VERSION 5.8 ;
BUSBITCHARS "[]" ;
DIVIDERCHAR "/" ;
UNITS
    DATABASE MICRONS 1000 ;
END UNITS

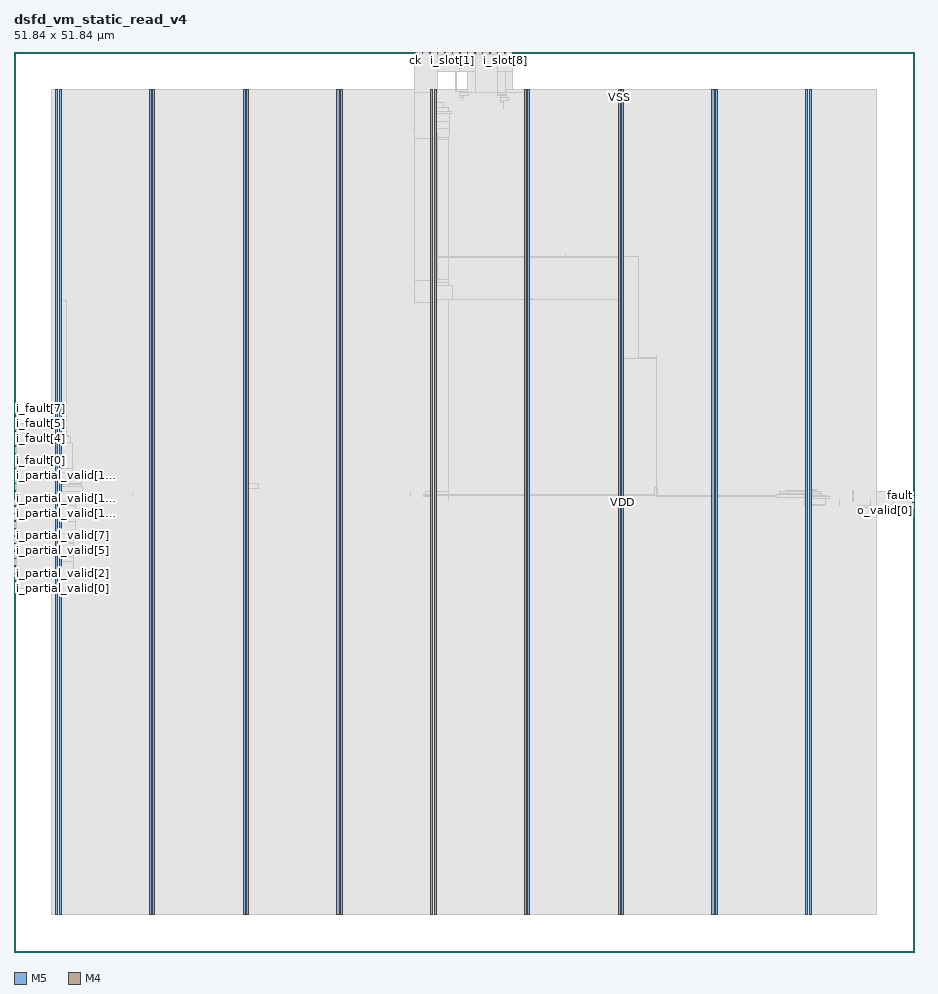
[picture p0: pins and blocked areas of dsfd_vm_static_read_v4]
MACRO dsfd_vm_static_read_v4
  FOREIGN dsfd_vm_static_read_v4 0 0 ;
  CLASS BLOCK ;
  SIZE 51.84 BY 51.84 ;
  PIN ck
    DIRECTION INPUT ;
    USE SIGNAL ;
    PORT
      LAYER M5 ;
        RECT  23.088 51.756 23.112 51.84 ;
    END
  END ck
  PIN fault
    DIRECTION OUTPUT ;
    USE SIGNAL ;
    PORT
      LAYER M4 ;
        RECT  51.756 26.304 51.84 26.328 ;
    END
  END fault
  PIN i_expected[0]
    DIRECTION INPUT ;
    USE SIGNAL ;
    PORT
      LAYER M5 ;
        RECT  23.952 51.756 23.976 51.84 ;
    END
  END i_expected[0]
  PIN i_expected[1]
    DIRECTION INPUT ;
    USE SIGNAL ;
    PORT
      LAYER M5 ;
        RECT  24.384 51.756 24.408 51.84 ;
    END
  END i_expected[1]
  PIN i_fault[0]
    DIRECTION INPUT ;
    USE SIGNAL ;
    PORT
      LAYER M4 ;
        RECT  0 27.84 0.084 27.864 ;
    END
  END i_fault[0]
  PIN i_fault[1]
    DIRECTION INPUT ;
    USE SIGNAL ;
    PORT
      LAYER M4 ;
        RECT  0 28.272 0.084 28.296 ;
    END
  END i_fault[1]
  PIN i_fault[2]
    DIRECTION INPUT ;
    USE SIGNAL ;
    PORT
      LAYER M4 ;
        RECT  0 28.704 0.084 28.728 ;
    END
  END i_fault[2]
  PIN i_fault[3]
    DIRECTION INPUT ;
    USE SIGNAL ;
    PORT
      LAYER M4 ;
        RECT  0 29.136 0.084 29.16 ;
    END
  END i_fault[3]
  PIN i_fault[4]
    DIRECTION INPUT ;
    USE SIGNAL ;
    PORT
      LAYER M4 ;
        RECT  0 29.568 0.084 29.592 ;
    END
  END i_fault[4]
  PIN i_fault[5]
    DIRECTION INPUT ;
    USE SIGNAL ;
    PORT
      LAYER M4 ;
        RECT  0 30 0.084 30.024 ;
    END
  END i_fault[5]
  PIN i_fault[6]
    DIRECTION INPUT ;
    USE SIGNAL ;
    PORT
      LAYER M4 ;
        RECT  0 30.432 0.084 30.456 ;
    END
  END i_fault[6]
  PIN i_fault[7]
    DIRECTION INPUT ;
    USE SIGNAL ;
    PORT
      LAYER M4 ;
        RECT  0 30.864 0.084 30.888 ;
    END
  END i_fault[7]
  PIN i_partial_valid[0]
    DIRECTION INPUT ;
    USE SIGNAL ;
    PORT
      LAYER M4 ;
        RECT  0 20.928 0.084 20.952 ;
    END
  END i_partial_valid[0]
  PIN i_partial_valid[10]
    DIRECTION INPUT ;
    USE SIGNAL ;
    PORT
      LAYER M4 ;
        RECT  0 25.248 0.084 25.272 ;
    END
  END i_partial_valid[10]
  PIN i_partial_valid[11]
    DIRECTION INPUT ;
    USE SIGNAL ;
    PORT
      LAYER M4 ;
        RECT  0 25.68 0.084 25.704 ;
    END
  END i_partial_valid[11]
  PIN i_partial_valid[12]
    DIRECTION INPUT ;
    USE SIGNAL ;
    PORT
      LAYER M4 ;
        RECT  0 26.112 0.084 26.136 ;
    END
  END i_partial_valid[12]
  PIN i_partial_valid[13]
    DIRECTION INPUT ;
    USE SIGNAL ;
    PORT
      LAYER M4 ;
        RECT  0 26.544 0.084 26.568 ;
    END
  END i_partial_valid[13]
  PIN i_partial_valid[14]
    DIRECTION INPUT ;
    USE SIGNAL ;
    PORT
      LAYER M4 ;
        RECT  0 26.976 0.084 27 ;
    END
  END i_partial_valid[14]
  PIN i_partial_valid[15]
    DIRECTION INPUT ;
    USE SIGNAL ;
    PORT
      LAYER M4 ;
        RECT  0 27.408 0.084 27.432 ;
    END
  END i_partial_valid[15]
  PIN i_partial_valid[1]
    DIRECTION INPUT ;
    USE SIGNAL ;
    PORT
      LAYER M4 ;
        RECT  0 21.36 0.084 21.384 ;
    END
  END i_partial_valid[1]
  PIN i_partial_valid[2]
    DIRECTION INPUT ;
    USE SIGNAL ;
    PORT
      LAYER M4 ;
        RECT  0 21.792 0.084 21.816 ;
    END
  END i_partial_valid[2]
  PIN i_partial_valid[3]
    DIRECTION INPUT ;
    USE SIGNAL ;
    PORT
      LAYER M4 ;
        RECT  0 22.224 0.084 22.248 ;
    END
  END i_partial_valid[3]
  PIN i_partial_valid[4]
    DIRECTION INPUT ;
    USE SIGNAL ;
    PORT
      LAYER M4 ;
        RECT  0 22.656 0.084 22.68 ;
    END
  END i_partial_valid[4]
  PIN i_partial_valid[5]
    DIRECTION INPUT ;
    USE SIGNAL ;
    PORT
      LAYER M4 ;
        RECT  0 23.088 0.084 23.112 ;
    END
  END i_partial_valid[5]
  PIN i_partial_valid[6]
    DIRECTION INPUT ;
    USE SIGNAL ;
    PORT
      LAYER M4 ;
        RECT  0 23.52 0.084 23.544 ;
    END
  END i_partial_valid[6]
  PIN i_partial_valid[7]
    DIRECTION INPUT ;
    USE SIGNAL ;
    PORT
      LAYER M4 ;
        RECT  0 23.952 0.084 23.976 ;
    END
  END i_partial_valid[7]
  PIN i_partial_valid[8]
    DIRECTION INPUT ;
    USE SIGNAL ;
    PORT
      LAYER M4 ;
        RECT  0 24.384 0.084 24.408 ;
    END
  END i_partial_valid[8]
  PIN i_partial_valid[9]
    DIRECTION INPUT ;
    USE SIGNAL ;
    PORT
      LAYER M4 ;
        RECT  0 24.816 0.084 24.84 ;
    END
  END i_partial_valid[9]
  PIN i_slot[0]
    DIRECTION INPUT ;
    USE SIGNAL ;
    PORT
      LAYER M5 ;
        RECT  24.816 51.756 24.84 51.84 ;
    END
  END i_slot[0]
  PIN i_slot[1]
    DIRECTION INPUT ;
    USE SIGNAL ;
    PORT
      LAYER M5 ;
        RECT  25.248 51.756 25.272 51.84 ;
    END
  END i_slot[1]
  PIN i_slot[2]
    DIRECTION INPUT ;
    USE SIGNAL ;
    PORT
      LAYER M5 ;
        RECT  25.68 51.756 25.704 51.84 ;
    END
  END i_slot[2]
  PIN i_slot[3]
    DIRECTION INPUT ;
    USE SIGNAL ;
    PORT
      LAYER M5 ;
        RECT  26.112 51.756 26.136 51.84 ;
    END
  END i_slot[3]
  PIN i_slot[4]
    DIRECTION INPUT ;
    USE SIGNAL ;
    PORT
      LAYER M5 ;
        RECT  26.544 51.756 26.568 51.84 ;
    END
  END i_slot[4]
  PIN i_slot[5]
    DIRECTION INPUT ;
    USE SIGNAL ;
    PORT
      LAYER M5 ;
        RECT  26.976 51.756 27 51.84 ;
    END
  END i_slot[5]
  PIN i_slot[6]
    DIRECTION INPUT ;
    USE SIGNAL ;
    PORT
      LAYER M5 ;
        RECT  27.408 51.756 27.432 51.84 ;
    END
  END i_slot[6]
  PIN i_slot[7]
    DIRECTION INPUT ;
    USE SIGNAL ;
    PORT
      LAYER M5 ;
        RECT  27.84 51.756 27.864 51.84 ;
    END
  END i_slot[7]
  PIN i_slot[8]
    DIRECTION INPUT ;
    USE SIGNAL ;
    PORT
      LAYER M5 ;
        RECT  28.272 51.756 28.296 51.84 ;
    END
  END i_slot[8]
  PIN i_slot[9]
    DIRECTION INPUT ;
    USE SIGNAL ;
    PORT
      LAYER M5 ;
        RECT  28.704 51.756 28.728 51.84 ;
    END
  END i_slot[9]
  PIN o_valid[0]
    DIRECTION OUTPUT ;
    USE SIGNAL ;
    PORT
      LAYER M4 ;
        RECT  51.756 25.44 51.84 25.464 ;
    END
  END o_valid[0]
  PIN o_valid[1]
    DIRECTION OUTPUT ;
    USE SIGNAL ;
    PORT
      LAYER M4 ;
        RECT  51.756 25.872 51.84 25.896 ;
    END
  END o_valid[1]
  PIN rst_n
    DIRECTION INPUT ;
    USE SIGNAL ;
    PORT
      LAYER M5 ;
        RECT  23.52 51.756 23.544 51.84 ;
    END
  END rst_n
  PIN VDD
    DIRECTION INOUT ;
    USE POWER ;
    PORT
      LAYER M5 ;
        RECT  45.792 2.151 45.912 49.689 ;
        RECT  40.392 2.151 40.512 49.689 ;
        RECT  34.992 2.151 35.112 49.689 ;
        RECT  29.592 2.151 29.712 49.689 ;
        RECT  24.192 2.151 24.312 49.689 ;
        RECT  18.792 2.151 18.912 49.689 ;
        RECT  13.392 2.151 13.512 49.689 ;
        RECT  7.992 2.151 8.112 49.689 ;
        RECT  2.592 2.151 2.712 49.689 ;
    END
  END VDD
  PIN VSS
    DIRECTION INOUT ;
    USE GROUND ;
    PORT
      LAYER M5 ;
        RECT  45.6 2.137 45.72 49.703 ;
        RECT  40.2 2.137 40.32 49.703 ;
        RECT  34.8 2.137 34.92 49.703 ;
        RECT  29.4 2.137 29.52 49.703 ;
        RECT  24 2.137 24.12 49.703 ;
        RECT  18.6 2.137 18.72 49.703 ;
        RECT  13.2 2.137 13.32 49.703 ;
        RECT  7.8 2.137 7.92 49.703 ;
        RECT  2.4 2.137 2.52 49.703 ;
    END
  END VSS
  # OT_OBS_CLOSED layer=M5 d_um=1.536 added=11
  OBS
    LAYER RVTN ;
     RECT  2.16 2.16 49.68 2.295 ;
     RECT  2.16 2.565 49.68 2.835 ;
     RECT  2.16 3.105 49.68 3.375 ;
     RECT  2.16 3.645 49.68 3.915 ;
     RECT  2.16 4.185 49.68 4.455 ;
     RECT  2.16 4.725 49.68 4.995 ;
     RECT  2.16 5.265 49.68 5.535 ;
     RECT  2.16 5.805 49.68 6.075 ;
     RECT  2.16 6.345 49.68 6.615 ;
     RECT  2.16 6.885 49.68 7.155 ;
     RECT  2.16 7.425 49.68 7.695 ;
     RECT  2.16 7.965 49.68 8.235 ;
     RECT  2.16 8.505 49.68 8.775 ;
     RECT  2.16 9.045 49.68 9.315 ;
     RECT  2.16 9.585 49.68 9.855 ;
     RECT  2.16 10.125 49.68 10.395 ;
     RECT  2.16 10.665 49.68 10.935 ;
     RECT  2.16 11.205 49.68 11.475 ;
     RECT  2.16 11.745 49.68 12.015 ;
     RECT  2.16 12.285 49.68 12.555 ;
     RECT  2.16 12.825 49.68 13.095 ;
     RECT  2.16 13.365 49.68 13.635 ;
     RECT  2.16 13.905 49.68 14.175 ;
     RECT  2.16 14.445 49.68 14.715 ;
     RECT  2.16 14.985 49.68 15.255 ;
     RECT  2.16 15.525 49.68 15.795 ;
     RECT  2.16 16.065 49.68 16.335 ;
     RECT  2.16 16.605 49.68 16.875 ;
     RECT  2.16 17.145 49.68 17.415 ;
     RECT  2.16 17.685 49.68 17.955 ;
     RECT  2.16 18.225 49.68 18.495 ;
     RECT  2.16 18.765 49.68 19.035 ;
     RECT  2.16 19.305 49.68 19.575 ;
     RECT  2.16 19.845 49.68 20.115 ;
     RECT  2.16 20.385 49.68 20.655 ;
     RECT  2.16 20.925 49.68 21.195 ;
     RECT  2.16 21.465 49.68 21.735 ;
     RECT  2.16 22.005 49.68 22.275 ;
     RECT  2.16 22.545 49.68 22.815 ;
     RECT  2.16 23.085 49.68 23.355 ;
     RECT  2.16 23.625 49.68 23.895 ;
     RECT  2.16 24.165 49.68 24.435 ;
     RECT  2.16 24.705 49.68 24.975 ;
     RECT  2.16 25.245 49.68 25.515 ;
     RECT  2.16 25.785 49.68 26.055 ;
     RECT  2.16 26.325 49.68 26.595 ;
     RECT  2.16 26.865 49.68 27.135 ;
     RECT  2.16 27.405 49.68 27.675 ;
     RECT  2.16 27.945 49.68 28.215 ;
     RECT  2.16 28.485 49.68 28.755 ;
     RECT  2.16 29.025 49.68 29.295 ;
     RECT  2.16 29.565 49.68 29.835 ;
     RECT  2.16 30.105 49.68 30.375 ;
     RECT  2.16 30.645 49.68 30.915 ;
     RECT  2.16 31.185 49.68 31.455 ;
     RECT  2.16 31.725 49.68 31.995 ;
     RECT  2.16 32.265 49.68 32.535 ;
     RECT  2.16 32.805 49.68 33.075 ;
     RECT  2.16 33.345 49.68 33.615 ;
     RECT  2.16 33.885 49.68 34.155 ;
     RECT  2.16 34.425 49.68 34.695 ;
     RECT  2.16 34.965 49.68 35.235 ;
     RECT  2.16 35.505 49.68 35.775 ;
     RECT  2.16 36.045 49.68 36.315 ;
     RECT  2.16 36.585 49.68 36.855 ;
     RECT  2.16 37.125 49.68 37.395 ;
     RECT  2.16 37.665 49.68 37.935 ;
     RECT  2.16 38.205 49.68 38.475 ;
     RECT  2.16 38.745 49.68 39.015 ;
     RECT  2.16 39.285 49.68 39.555 ;
     RECT  2.16 39.825 49.68 40.095 ;
     RECT  2.16 40.365 49.68 40.635 ;
     RECT  2.16 40.905 49.68 41.175 ;
     RECT  2.16 41.445 49.68 41.715 ;
     RECT  2.16 41.985 49.68 42.255 ;
     RECT  2.16 42.525 49.68 42.795 ;
     RECT  2.16 43.065 49.68 43.335 ;
     RECT  2.16 43.605 49.68 43.875 ;
     RECT  2.16 44.145 49.68 44.415 ;
     RECT  2.16 44.685 49.68 44.955 ;
     RECT  2.16 45.225 49.68 45.495 ;
     RECT  2.16 45.765 49.68 46.035 ;
     RECT  2.16 46.305 49.68 46.575 ;
     RECT  2.16 46.845 49.68 47.115 ;
     RECT  2.16 47.385 49.68 47.655 ;
     RECT  2.16 47.925 49.68 48.195 ;
     RECT  2.16 48.465 49.68 48.735 ;
     RECT  2.16 49.005 49.68 49.275 ;
     RECT  2.16 49.545 49.68 49.68 ;
    LAYER RVTP ;
     RECT  2.16 2.295 49.68 2.565 ;
     RECT  2.16 2.835 49.68 3.105 ;
     RECT  2.16 3.375 49.68 3.645 ;
     RECT  2.16 3.915 49.68 4.185 ;
     RECT  2.16 4.455 49.68 4.725 ;
     RECT  2.16 4.995 49.68 5.265 ;
     RECT  2.16 5.535 49.68 5.805 ;
     RECT  2.16 6.075 49.68 6.345 ;
     RECT  2.16 6.615 49.68 6.885 ;
     RECT  2.16 7.155 49.68 7.425 ;
     RECT  2.16 7.695 49.68 7.965 ;
     RECT  2.16 8.235 49.68 8.505 ;
     RECT  2.16 8.775 49.68 9.045 ;
     RECT  2.16 9.315 49.68 9.585 ;
     RECT  2.16 9.855 49.68 10.125 ;
     RECT  2.16 10.395 49.68 10.665 ;
     RECT  2.16 10.935 49.68 11.205 ;
     RECT  2.16 11.475 49.68 11.745 ;
     RECT  2.16 12.015 49.68 12.285 ;
     RECT  2.16 12.555 49.68 12.825 ;
     RECT  2.16 13.095 49.68 13.365 ;
     RECT  2.16 13.635 49.68 13.905 ;
     RECT  2.16 14.175 49.68 14.445 ;
     RECT  2.16 14.715 49.68 14.985 ;
     RECT  2.16 15.255 49.68 15.525 ;
     RECT  2.16 15.795 49.68 16.065 ;
     RECT  2.16 16.335 49.68 16.605 ;
     RECT  2.16 16.875 49.68 17.145 ;
     RECT  2.16 17.415 49.68 17.685 ;
     RECT  2.16 17.955 49.68 18.225 ;
     RECT  2.16 18.495 49.68 18.765 ;
     RECT  2.16 19.035 49.68 19.305 ;
     RECT  2.16 19.575 49.68 19.845 ;
     RECT  2.16 20.115 49.68 20.385 ;
     RECT  2.16 20.655 49.68 20.925 ;
     RECT  2.16 21.195 49.68 21.465 ;
     RECT  2.16 21.735 49.68 22.005 ;
     RECT  2.16 22.275 49.68 22.545 ;
     RECT  2.16 22.815 49.68 23.085 ;
     RECT  2.16 23.355 49.68 23.625 ;
     RECT  2.16 23.895 49.68 24.165 ;
     RECT  2.16 24.435 49.68 24.705 ;
     RECT  2.16 24.975 49.68 25.245 ;
     RECT  2.16 25.515 49.68 25.785 ;
     RECT  2.16 26.055 49.68 26.325 ;
     RECT  2.16 26.595 49.68 26.865 ;
     RECT  2.16 27.135 49.68 27.405 ;
     RECT  2.16 27.675 49.68 27.945 ;
     RECT  2.16 28.215 49.68 28.485 ;
     RECT  2.16 28.755 49.68 29.025 ;
     RECT  2.16 29.295 49.68 29.565 ;
     RECT  2.16 29.835 49.68 30.105 ;
     RECT  2.16 30.375 49.68 30.645 ;
     RECT  2.16 30.915 49.68 31.185 ;
     RECT  2.16 31.455 49.68 31.725 ;
     RECT  2.16 31.995 49.68 32.265 ;
     RECT  2.16 32.535 49.68 32.805 ;
     RECT  2.16 33.075 49.68 33.345 ;
     RECT  2.16 33.615 49.68 33.885 ;
     RECT  2.16 34.155 49.68 34.425 ;
     RECT  2.16 34.695 49.68 34.965 ;
     RECT  2.16 35.235 49.68 35.505 ;
     RECT  2.16 35.775 49.68 36.045 ;
     RECT  2.16 36.315 49.68 36.585 ;
     RECT  2.16 36.855 49.68 37.125 ;
     RECT  2.16 37.395 49.68 37.665 ;
     RECT  2.16 37.935 49.68 38.205 ;
     RECT  2.16 38.475 49.68 38.745 ;
     RECT  2.16 39.015 49.68 39.285 ;
     RECT  2.16 39.555 49.68 39.825 ;
     RECT  2.16 40.095 49.68 40.365 ;
     RECT  2.16 40.635 49.68 40.905 ;
     RECT  2.16 41.175 49.68 41.445 ;
     RECT  2.16 41.715 49.68 41.985 ;
     RECT  2.16 42.255 49.68 42.525 ;
     RECT  2.16 42.795 49.68 43.065 ;
     RECT  2.16 43.335 49.68 43.605 ;
     RECT  2.16 43.875 49.68 44.145 ;
     RECT  2.16 44.415 49.68 44.685 ;
     RECT  2.16 44.955 49.68 45.225 ;
     RECT  2.16 45.495 49.68 45.765 ;
     RECT  2.16 46.035 49.68 46.305 ;
     RECT  2.16 46.575 49.68 46.845 ;
     RECT  2.16 47.115 49.68 47.385 ;
     RECT  2.16 47.655 49.68 47.925 ;
     RECT  2.16 48.195 49.68 48.465 ;
     RECT  2.16 48.735 49.68 49.005 ;
     RECT  2.16 49.275 49.68 49.545 ;
    LAYER M1 ;
     RECT  2.16 2.151 49.68 49.689 ;
    LAYER M2 ;
     RECT  0.103 29.034 0.139 29.052 ;
     RECT  0.103 25.02 2.16 25.038 ;
     RECT  0.031 25.992 2.16 26.01 ;
     RECT  0.103 27.342 2.16 27.36 ;
     RECT  0.139 28.8 2.16 29.052 ;
     RECT  0.103 30.15 2.16 30.168 ;
     RECT  2.16 2.151 49.68 49.689 ;
     RECT  49.68 25.326 50.711 26.514 ;
    LAYER M3 ;
     RECT  2.415 2.143 2.505 2.413 ;
     RECT  7.815 2.143 7.905 2.413 ;
     RECT  13.215 2.143 13.305 2.413 ;
     RECT  18.615 2.143 18.705 2.413 ;
     RECT  24.015 2.143 24.105 2.413 ;
     RECT  29.415 2.143 29.505 2.413 ;
     RECT  34.815 2.143 34.905 2.413 ;
     RECT  40.215 2.143 40.305 2.413 ;
     RECT  45.615 2.143 45.705 2.413 ;
     RECT  2.415 2.413 2.697 20.923 ;
     RECT  0.108 21.355 0.126 21.643 ;
     RECT  0.036 21.643 0.126 21.677 ;
     RECT  2.304 20.923 2.697 22.513 ;
     RECT  3.42 21.811 3.438 22.513 ;
     RECT  2.304 22.513 3.438 22.775 ;
     RECT  2.415 22.775 3.438 23.515 ;
     RECT  2.304 23.515 3.438 23.585 ;
     RECT  2.415 23.585 3.438 24.133 ;
     RECT  2.415 24.133 3.546 24.811 ;
     RECT  0.036 21.677 0.054 25.015 ;
     RECT  49.356 25.285 49.374 25.411 ;
     RECT  49.32 25.411 49.374 25.591 ;
     RECT  48.672 25.591 49.374 25.709 ;
     RECT  45.615 2.413 45.897 25.717 ;
     RECT  45.615 25.717 46.602 25.723 ;
     RECT  2.304 24.811 3.546 25.745 ;
     RECT  45.54 25.723 46.602 25.753 ;
     RECT  2.415 25.745 3.546 25.951 ;
     RECT  0.036 25.015 0.126 26.015 ;
     RECT  47.52 25.717 47.538 26.015 ;
     RECT  48.276 25.951 48.33 26.051 ;
     RECT  49.32 25.709 49.338 26.051 ;
     RECT  45.54 25.753 46.746 26.131 ;
     RECT  0.108 26.015 0.126 26.141 ;
     RECT  45.54 26.131 46.998 26.249 ;
     RECT  24.015 2.413 24.297 26.257 ;
     RECT  43.92 26.155 43.938 26.257 ;
     RECT  45.54 26.249 46.854 26.285 ;
     RECT  23.58 26.257 24.297 26.293 ;
     RECT  25.02 25.987 25.038 26.293 ;
     RECT  23.58 26.293 25.038 26.333 ;
     RECT  43.848 26.257 44.658 26.333 ;
     RECT  6.804 26.293 6.822 26.393 ;
     RECT  44.1 26.333 44.658 26.401 ;
     RECT  45.54 26.285 46.494 26.401 ;
     RECT  2.415 25.951 3.978 26.519 ;
     RECT  22.824 26.293 22.842 26.519 ;
     RECT  23.724 26.333 25.038 26.519 ;
     RECT  44.1 26.401 46.494 26.519 ;
     RECT  50.688 25.321 50.706 26.519 ;
     RECT  44.496 26.519 46.206 26.555 ;
     RECT  48.312 26.051 48.33 26.555 ;
     RECT  44.496 26.555 44.514 26.627 ;
     RECT  45.615 26.555 46.206 26.627 ;
     RECT  13.215 2.413 13.497 26.671 ;
     RECT  2.415 26.519 3.942 26.789 ;
     RECT  2.415 26.789 3.87 26.905 ;
     RECT  13.215 26.671 14.058 26.969 ;
     RECT  2.304 26.905 3.87 27.005 ;
     RECT  0.108 27.337 0.126 27.437 ;
     RECT  2.415 27.005 3.87 27.599 ;
     RECT  2.415 27.599 3.366 27.835 ;
     RECT  0.144 28.795 0.162 29.029 ;
     RECT  0.108 29.029 0.162 29.165 ;
     RECT  2.304 27.835 3.366 29.363 ;
     RECT  2.304 29.363 3.258 29.669 ;
     RECT  2.304 29.669 3.15 29.759 ;
     RECT  2.304 29.759 3.042 29.795 ;
     RECT  0.144 29.165 0.162 30.029 ;
     RECT  2.415 29.795 3.042 30.299 ;
     RECT  0.108 30.145 0.126 30.893 ;
     RECT  36.504 34.159 36.522 34.205 ;
     RECT  37.008 34.219 37.026 34.385 ;
     RECT  2.415 30.299 3.006 37.499 ;
     RECT  24.015 26.519 25.038 37.561 ;
     RECT  34.815 2.413 35.097 37.561 ;
     RECT  29.415 2.413 29.697 37.579 ;
     RECT  34.812 37.561 35.097 37.613 ;
     RECT  29.415 37.579 29.79 37.625 ;
     RECT  35.928 37.579 35.946 37.625 ;
     RECT  24.015 37.561 25.254 38.399 ;
     RECT  24.015 38.399 25.038 38.551 ;
     RECT  23.976 38.551 25.038 38.717 ;
     RECT  31.752 40.027 31.878 40.064 ;
     RECT  31.752 40.064 31.77 40.199 ;
     RECT  24.015 38.717 25.038 46.777 ;
     RECT  23.796 46.777 25.038 46.921 ;
     RECT  23.04 47.317 23.058 47.461 ;
     RECT  23.796 46.921 25.074 47.461 ;
     RECT  23.04 47.461 25.074 47.849 ;
     RECT  23.364 47.849 25.074 48.271 ;
     RECT  23.364 48.271 25.218 48.389 ;
     RECT  23.364 48.389 25.074 48.425 ;
     RECT  23.364 48.425 25.038 48.659 ;
     RECT  23.364 48.659 24.714 48.929 ;
     RECT  28.188 48.541 28.206 48.937 ;
     RECT  28.044 48.937 28.206 49.045 ;
     RECT  28.044 49.045 28.494 49.199 ;
     RECT  25.812 49.045 25.83 49.207 ;
     RECT  25.632 49.207 25.83 49.243 ;
     RECT  25.632 49.243 25.866 49.315 ;
     RECT  28.044 49.199 28.386 49.315 ;
     RECT  27.9 49.315 28.386 49.373 ;
     RECT  2.415 37.499 2.697 49.427 ;
     RECT  7.815 2.413 8.097 49.427 ;
     RECT  13.215 26.969 13.497 49.427 ;
     RECT  18.615 2.413 18.897 49.427 ;
     RECT  23.364 48.929 24.297 49.427 ;
     RECT  29.415 37.625 29.697 49.427 ;
     RECT  34.815 37.613 35.097 49.427 ;
     RECT  40.215 2.413 40.497 49.427 ;
     RECT  45.615 26.627 45.897 49.427 ;
     RECT  25.632 49.315 26.154 49.531 ;
     RECT  25.632 49.531 26.334 49.549 ;
     RECT  25.452 49.549 26.334 49.565 ;
     RECT  23.364 49.427 24.282 49.577 ;
     RECT  26.316 49.565 26.334 49.577 ;
     RECT  28.044 49.373 28.386 49.577 ;
     RECT  2.415 49.427 2.505 49.697 ;
     RECT  7.815 49.427 7.905 49.697 ;
     RECT  13.215 49.427 13.305 49.697 ;
     RECT  18.615 49.427 18.705 49.697 ;
     RECT  23.976 49.577 24.105 49.697 ;
     RECT  29.415 49.427 29.505 49.697 ;
     RECT  34.815 49.427 34.905 49.697 ;
     RECT  40.215 49.427 40.305 49.697 ;
     RECT  45.615 49.427 45.705 49.697 ;
     RECT  23.976 49.697 23.994 49.853 ;
     RECT  25.452 49.565 25.47 50.765 ;
     RECT  28.368 49.577 28.386 50.765 ;
    LAYER M4 ;
     RECT  0.025 21.648 0.06 21.672 ;
     RECT  0.06 20.928 0.137 30.888 ;
     RECT  0.137 20.928 2.408 30.456 ;
     RECT  2.408 2.148 2.512 49.692 ;
     RECT  2.512 2.418 2.704 49.422 ;
     RECT  7.808 2.148 7.912 49.692 ;
     RECT  7.912 2.418 8.104 49.422 ;
     RECT  13.208 2.148 13.312 49.692 ;
     RECT  13.312 2.418 13.504 49.422 ;
     RECT  18.608 2.148 18.712 49.692 ;
     RECT  18.712 2.418 18.904 49.422 ;
     RECT  23.461 49.536 23.756 49.56 ;
     RECT  23.029 47.328 23.785 47.352 ;
     RECT  23.756 48.768 23.941 49.56 ;
     RECT  23.569 26.304 24.008 26.328 ;
     RECT  23.077 37.44 24.008 37.464 ;
     RECT  23.965 38.688 24.008 38.712 ;
     RECT  23.785 46.8 24.008 47.352 ;
     RECT  23.941 48.768 24.008 49.848 ;
     RECT  24.008 2.148 24.028 49.848 ;
     RECT  24.028 2.148 24.112 49.692 ;
     RECT  24.112 2.418 24.304 49.56 ;
     RECT  24.304 37.44 24.401 37.608 ;
     RECT  24.304 38.688 24.419 38.712 ;
     RECT  24.304 46.8 24.419 47.16 ;
     RECT  24.304 49.536 24.419 49.56 ;
     RECT  24.419 47.136 24.437 47.16 ;
     RECT  25.441 50.736 25.715 50.76 ;
     RECT  25.729 49.536 26.579 49.56 ;
     RECT  27.829 49.344 27.929 49.368 ;
     RECT  28.033 49.536 28.307 49.56 ;
     RECT  28.357 50.736 28.739 50.76 ;
     RECT  24.304 26.304 29.408 26.328 ;
     RECT  24.401 37.584 29.408 37.608 ;
     RECT  24.304 40.032 29.408 40.056 ;
     RECT  29.408 2.148 29.512 49.692 ;
     RECT  29.512 2.418 29.704 49.422 ;
     RECT  29.704 26.304 34.808 26.328 ;
     RECT  29.704 37.584 34.808 37.608 ;
     RECT  29.704 40.032 34.808 40.056 ;
     RECT  34.808 2.148 34.912 49.692 ;
     RECT  34.912 2.418 35.104 49.422 ;
     RECT  35.104 37.584 35.987 37.608 ;
     RECT  35.104 40.032 35.987 40.056 ;
     RECT  35.104 34.176 36.533 34.2 ;
     RECT  35.104 26.304 36.901 26.328 ;
     RECT  36.901 26.304 36.997 26.76 ;
     RECT  36.997 26.256 37.043 26.76 ;
     RECT  36.956 34.224 37.043 34.248 ;
     RECT  37.043 26.256 40.208 26.28 ;
     RECT  40.208 2.148 40.312 49.692 ;
     RECT  40.312 2.418 40.504 49.422 ;
     RECT  40.504 26.256 43.837 26.28 ;
     RECT  43.837 26.256 43.909 26.328 ;
     RECT  43.909 26.16 45.529 26.328 ;
     RECT  45.529 25.728 45.608 26.328 ;
     RECT  45.608 2.148 45.712 49.692 ;
     RECT  45.712 2.418 45.904 49.422 ;
     RECT  45.904 25.728 46.613 25.752 ;
     RECT  50.677 25.44 51.804 26.328 ;
    LAYER M5 ;
     RECT  2.4 2.137 2.52 2.151 ;
     RECT  7.8 2.137 7.92 2.151 ;
     RECT  13.2 2.137 13.32 2.151 ;
     RECT  18.6 2.137 18.72 2.151 ;
     RECT  24 2.137 24.12 2.151 ;
     RECT  29.4 2.137 29.52 2.151 ;
     RECT  34.8 2.137 34.92 2.151 ;
     RECT  40.2 2.137 40.32 2.151 ;
     RECT  45.6 2.137 45.72 2.151 ;
     RECT  37.008 26.245 37.032 26.293 ;
     RECT  36.912 26.293 37.032 26.771 ;
     RECT  34.8 2.151 35.112 34.165 ;
     RECT  37.008 26.771 37.032 34.259 ;
     RECT  24 2.151 24.312 37.429 ;
     RECT  23.088 37.429 24.312 38.677 ;
     RECT  34.8 34.165 35.976 40.067 ;
     RECT  23.088 38.677 24.408 46.835 ;
     RECT  23.088 46.835 24.312 49.525 ;
     RECT  27.84 49.333 27.864 49.525 ;
     RECT  2.4 2.151 2.712 49.689 ;
     RECT  7.8 2.151 8.112 49.689 ;
     RECT  13.2 2.151 13.512 49.689 ;
     RECT  18.6 2.151 18.912 49.689 ;
     RECT  29.4 2.151 29.712 49.689 ;
     RECT  34.8 40.067 35.112 49.689 ;
     RECT  40.2 2.151 40.512 49.689 ;
     RECT  45.6 2.151 45.912 49.689 ;
     RECT  2.4 49.689 2.52 49.703 ;
     RECT  7.8 49.689 7.92 49.703 ;
     RECT  13.2 49.689 13.32 49.703 ;
     RECT  18.6 49.689 18.72 49.703 ;
     RECT  29.4 49.689 29.52 49.703 ;
     RECT  34.8 49.689 34.92 49.703 ;
     RECT  40.2 49.689 40.32 49.703 ;
     RECT  45.6 49.689 45.72 49.703 ;
     RECT  26.112 49.525 26.568 50.725 ;
     RECT  27.84 49.525 28.296 50.725 ;
     RECT  23.088 49.525 24.408 51.792 ;
     RECT  25.68 50.725 26.568 51.792 ;
     RECT  27.84 50.725 28.728 51.792 ;
     RECT  35.976 34.165 37.008 34.259 ;
     RECT  26.568 49.525 27.84 51.708 ;
     RECT  28.296 49.525 29.4 49.703 ;
     RECT  28.296 49.703 28.728 50.725 ;
     RECT  24.408 50.725 25.68 51.708 ;
     RECT  24.456 51.708 24.768 51.792 ;
     RECT  24.888 51.708 25.2 51.792 ;
     RECT  25.32 51.708 25.632 51.792 ;
     RECT  26.616 51.708 26.928 51.792 ;
     RECT  27.048 51.708 27.36 51.792 ;
     RECT  27.48 51.708 27.792 51.792 ;
  END
END dsfd_vm_static_read_v4
END LIBRARY
